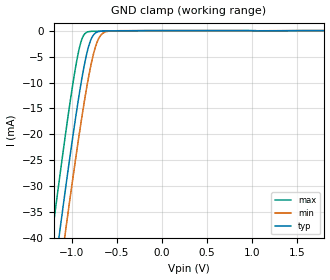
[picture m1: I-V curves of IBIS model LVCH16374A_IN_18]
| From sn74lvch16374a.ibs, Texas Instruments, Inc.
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[Model]   LVCH16374A_IN_18
Model_type  Input
Vinl=0.5775
Vinh=1.2675
| variable   typ   min   max
C_comp   3.69pF   3.02pF   4.47pF
[Temperature Range]   40   100   -40
| Ambient temperature   25   85   -40
[Voltage range]   1.8   1.65   1.95
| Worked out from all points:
|   GND clamp passes 1 mA (typ) near -0.76 V on its own axis
[GND Clamp]
| LVCH16374A_IN_18
|   Voltage   I(typ)   I(min)   I(max)
-5.5V     -656.5mA   -663.3mA   -648.2mA
-1.215V   -49.77mA   -58.01mA   -39.22mA
-1.135V   -39.23mA   -47.47mA   -28.65mA
-1.075V   -31.49mA   -39.7mA    -20.97mA
-1.055V   -28.95mA   -37.15mA   -18.47mA
-955mV    -16.79mA   -24.74mA   -7.045mA
-885mV    -9.193mA   -16.61mA   -1.637mA
-835mV    -4.741mA   -11.3mA    -351.3uA
-785mV    -1.746mA   -6.679mA   -145.9uA
-715mV    -270.3uA   -2.162mA   -107.4uA
-650mV    -78.21uA   -471.6uA   -91.29uA
1.8V      5.126pA    37.8nA     -54.32pA
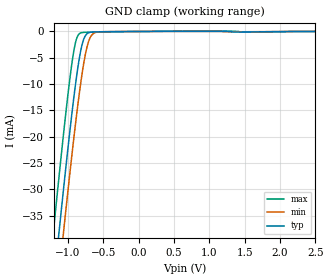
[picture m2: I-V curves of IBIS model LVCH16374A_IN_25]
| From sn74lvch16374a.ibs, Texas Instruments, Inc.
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[Model]   LVCH16374A_IN_25
Model_type  Input
Vinl=0.7
Vinh=1.7
| variable   typ   min   max
C_comp   3.65pF   3.04pF   4.50pF
[Temperature Range]   40   100   -40
| Ambient temperature   25   85   -40
[Voltage range]   2.5   2.3   2.7
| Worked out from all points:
|   GND clamp passes 1 mA (typ) near -0.76 V on its own axis
[GND Clamp]
| LVCH16374A_IN_25
|   Voltage   I(typ)   I(min)   I(max)
-5.5V     -656.6mA   -663.4mA   -648.4mA
-1.205V   -48.49mA   -56.72mA   -37.95mA
-1.13V    -38.62mA   -46.85mA   -28.06mA
-1.07V    -30.89mA   -39.1mA    -20.39mA
-1.055V   -28.99mA   -37.18mA   -18.53mA
-965mV    -17.99mA   -25.98mA   -8.114mA
-885mV    -9.23mA    -16.64mA   -1.681mA
-825mV    -4.04mA    -10.34mA   -313.2uA
-775mV    -1.398mA   -5.9mA     -175.3uA
-710mV    -268.9uA   -1.977mA   -144.6uA
-640mV    -98.59uA   -388.9uA   -125.6uA
2.5V      7.214pA    38.93nA    -770.4pA
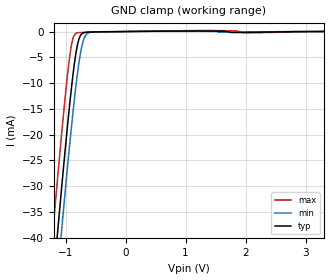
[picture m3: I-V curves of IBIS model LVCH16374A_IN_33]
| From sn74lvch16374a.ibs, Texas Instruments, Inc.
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[Model]   LVCH16374A_IN_33
Model_type  Input
Vinl=0.8
Vinh=2.0
| variable   typ   min   max
C_comp   3.58pF   2.85pF   4.58pF
[Temperature Range]   40   100   -40
| Ambient temperature   25   85   -40
[Voltage range]   3.3   3   3.6
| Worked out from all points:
|   GND clamp passes 1 mA (typ) near -0.76 V on its own axis
[GND Clamp]
| LVCH16374A_IN_33
|   Voltage   I(typ)   I(min)   I(max)
-5.5V     -656.7mA   -663.4mA   -648.5mA
-1.22V    -50.53mA   -58.75mA   -40.01mA
-1.14V    -39.97mA   -48.19mA   -29.42mA
-1.08V    -32.21mA   -40.41mA   -21.7mA
-1.06V    -29.67mA   -37.85mA   -19.2mA
-965mV    -18.03mA   -26.01mA   -8.161mA
-885mV    -9.265mA   -16.67mA   -1.724mA
-830mV    -4.433mA   -10.86mA   -391.1uA
-775mV    -1.429mA   -5.924mA   -215.8uA
-715mV    -330.4uA   -2.212mA   -184.8uA
-640mV    -124.8uA   -410.1uA   -161.8uA
3.3V      9.604pA    40.59nA    -142.9nA
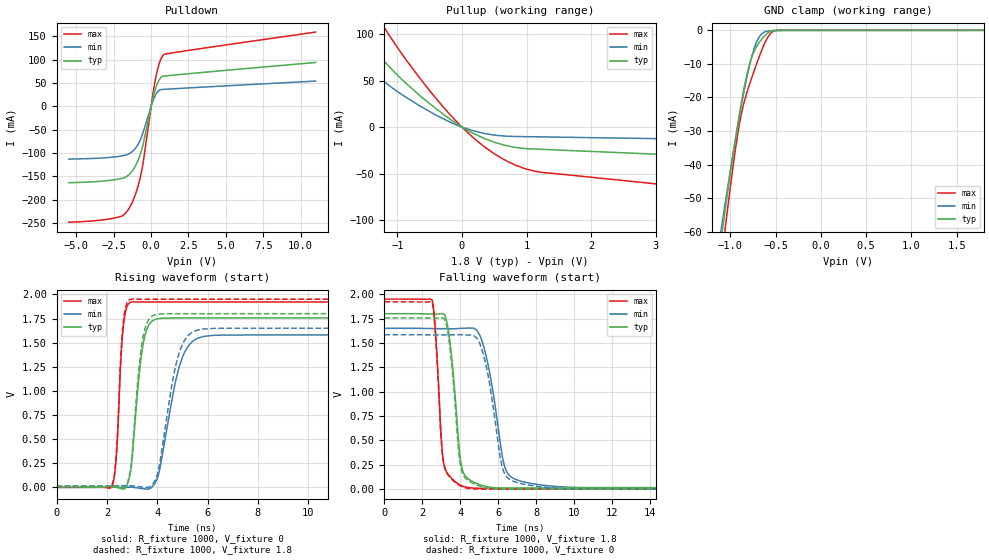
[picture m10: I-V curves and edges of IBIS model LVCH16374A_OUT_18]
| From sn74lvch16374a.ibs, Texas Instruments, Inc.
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[Model]   LVCH16374A_OUT_18
Model_type  3-state
Enable   Active-Low
Vref =   0
Rref =   1000
Cref =   30p
Vmeas =   0.9
| variable   typ   min   max
C_comp   5.26pF   4.69pF   6.09pF
| C_pullup   6.10pF   5.53pF   6.75pF
| C_pulldown   8.32pF   6.62pF   10.15pF
| C_tri-state   5.26pF   4.69pF   6.09pF
[Temperature Range]   40   100   -40
| Ambient temperature   25   85   -40
[Voltage range]   1.8   1.65   1.95
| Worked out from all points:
|   slope of the pulldown table from 0 to 0.27 V, typ, clamps not added: 7.65 ohm
|   slope of the pullup table from 0 to 0.27 V, typ, clamps not added: 27.4 ohm
|   GND clamp passes 1 mA (typ) near -0.60 V on its own axis
|   rising waveform, R_fixture 1000, V_fixture 0: 20-80 % time 372ps typ, 704ps min, 217ps max; typ from 0 V to 1.76 V
|   falling waveform, R_fixture 1000, V_fixture 1.8: 20-80 % time 471ps typ, 803ps min, 336ps max; typ from 1.8 V to 0.012 V
|   rising waveform, R_fixture 1000, V_fixture 1.8: 20-80 % time 356ps typ, 637ps min, 215ps max; typ from 0.012 V to 1.8 V
|   falling waveform, R_fixture 1000, V_fixture 0: 20-80 % time 456ps typ, 758ps min, 333ps max; typ from 1.76 V to 0 V
[GND Clamp]
| LVCH16374A_OUT_18
|   Voltage   I(typ)   I(min)   I(max)
-5.5V     -1.092A    -985.9mA   -1.265A
-1.12V    -65.63mA   -62.5mA    -73.1mA
-1.09V    -59.68mA   -57.14mA   -66.23mA
-1.06V    -53.82mA   -51.86mA   -59.48mA
-1.045V   -50.92mA   -49.25mA   -56.15mA
-960mV    -35.13mA   -34.95mA   -38.34mA
-900mV    -24.87mA   -25.49mA   -27.8mA
-795mV    -10.66mA   -11.13mA   -16.59mA
-735mV    -6.119mA   -5.16mA    -11.82mA
-685mV    -3.765mA   -2.107mA   -8.076mA
-535mV    -84.46uA   -113.4uA   -414.9uA
1.8V      37.82pA    12.05nA    -2.548nA
[Pulldown]
| LVCH16374A_OUT_18
|   Voltage   I(typ)   I(min)   I(max)
-5.5V     -163.6mA   -113mA     -248.3mA
-2.075V   -155.2mA   -106.7mA   -236.5mA
-1.745V   -152.2mA   -104.6mA   -230mA
-1.42V    -144.4mA   -100.5mA   -215.8mA
-1.03V    -126.4mA   -88.99mA   -186.9mA
-695mV    -100.2mA   -69.99mA   -148.2mA
-520mV    -79.1mA    -54.01mA   -118mA
70mV      10.47mA    6.993mA    15.91mA
275mV     35.8mA     23.13mA    55.48mA
565mV     58.22mA    35.03mA    93.73mA
855mV     65.08mA    36.56mA    111.2mA
11V       94.21mA    54.33mA    159.3mA
[Pullup]
| LVCH16374A_OUT_18
|   Voltage   I(typ)   I(min)   I(max)
-5.5V     76.47mA    21.29mA    197.6mA
-4.37V    108.6mA    28.72mA    361.1mA
-3.855V   218mA      37.63mA    399.7mA
-3.525V   246.1mA    54.36mA    367.6mA
-3.375V   237.1mA    101mA      351.9mA
-3.29V    231.5mA    135mA      342.8mA
-2.44V    168.1mA    121.7mA    247.7mA
-1.665V   107.2mA    76.55mA    159.2mA
-1.23V    72.83mA    50.5mA     110mA
-15mV     641.2uA    386.5uA    1.048mA
1.12V     -23.55mA   -10.38mA   -47.39mA
11V       -53.91mA   -20.99mA   -120.9mA
[Ramp]
| LVCH16374A_OUT_18
| variable   typ   min   max
dV/dt_r   1.07/3.86E-10   0.96/7.13E-10   1.16/2.28E-10
dV/dt_f   1.07/4.78E-10   0.98/8.08E-10   1.17/3.40E-10
R_load = 1000
[Rising Waveform]
| LVCH16374A_OUT_18
R_fixture =   1000
C_fixture =   0
L_fixture =   0
V_fixture =   0
V_fixture_min = 0
V_fixture_max = 0
|   Time   V(typ)   V(min)   V(max)
0s        559.4pV    2.27nV     20.29nV
2.21ns    1.77mV     809.6uV    14.88mV
2.385ns   -540.1uV   1.305mV    360.4mV
2.665ns   -18.66mV   2.068mV    1.695V
3.005ns   306.6mV    967uV      1.922V
3.34ns    1.304V     -10.67mV   1.921V
3.64ns    1.669V     -17.95mV   1.921V
5ns       1.756V     1.347V     1.922V
5.98ns    1.756V     1.569V     1.922V
50ns      1.756V     1.58V      1.922V
[Falling Waveform]
| LVCH16374A_OUT_18
R_fixture =   1000
C_fixture =   0
L_fixture =   0
V_fixture =   1.8
V_fixture_min = 1.65
V_fixture_max = 1.95
|   Time   V(typ)   V(min)   V(max)
0s        1.8V       1.65V      1.95V
2.52ns    1.797V     1.647V     1.936V
3.185ns   1.782V     1.646V     223.1mV
3.52ns    1.402V     1.645V     116mV
4.005ns   309.3mV    1.649V     42.17mV
4.36ns    116.5mV    1.652V     18.87mV
5.26ns    32.13mV    1.447V     8.808mV
6.405ns   12.35mV    198.4mV    8.419mV
7.69ns    11.7mV     59.94mV    8.361mV
50ns      11.53mV    15.73mV    8.262mV
[Rising Waveform]
| LVCH16374A_OUT_18
R_fixture =   1000
C_fixture =   0
L_fixture =   0
V_fixture =   1.8
V_fixture_min = 1.65
V_fixture_max = 1.95
|   Time   V(typ)   V(min)   V(max)
0s        11.51mV    15.68mV    8.257mV
2.21ns    13.06mV    16.42mV    24.1mV
2.38ns    10.83mV    16.81mV    368.8mV
2.645ns   -6.565mV   17.33mV    1.692V
2.995ns   316.3mV    16.11mV    1.951V
3.615ns   1.718V     -234.7uV   1.95V
4.045ns   1.795V     177mV      1.95V
4.9ns     1.8V       1.415V     1.95V
5.8ns     1.8V       1.64V      1.95V
50ns      1.8V       1.65V      1.95V
[Falling Waveform]
| LVCH16374A_OUT_18
R_fixture =   1000
C_fixture =   0
L_fixture =   0
V_fixture =   0
V_fixture_min = 0
V_fixture_max = 0
|   Time   V(typ)   V(min)   V(max)
0s        1.758V     1.585V     1.922V
2.52ns    1.755V     1.583V     1.908V
3.175ns   1.738V     1.583V     219.1mV
3.5ns     1.375V     1.583V     112.6mV
3.98ns    283.9mV    1.585V     37.03mV
4.37ns    96.15mV    1.582V     10.47mV
5.23ns    20.32mV    1.374V     560uV
6.3ns     901uV      177.1mV    173.9uV
7.565ns   200uV      42.86mV    104.6uV
50ns      12.16uV    48.19uV    4.972uV
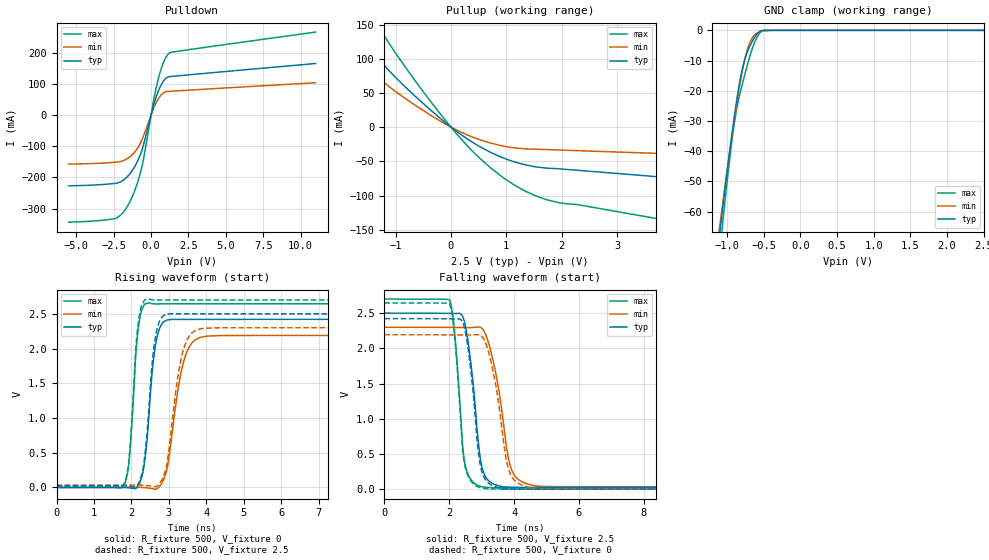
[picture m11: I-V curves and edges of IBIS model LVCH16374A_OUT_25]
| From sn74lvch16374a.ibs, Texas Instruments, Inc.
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[Model]   LVCH16374A_OUT_25
Model_type  3-state
Enable   Active-Low
Vref =   0
Rref =   500
Cref =   30p
Vmeas =   1.25
| variable   typ   min   max
C_comp   5.07pF   4.45pF   6.04pF
| C_pullup   5.99pF   5.35pF   6.80pF
| C_pulldown   7.61pF   6.27pF   8.94pF
| C_tri-state   5.07pF   4.45pF   6.04pF
[Temperature Range]   40   100   -40
| Ambient temperature   25   85   -40
[Voltage range]   2.5   2.3   2.7
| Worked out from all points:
|   slope of the pulldown table from 0 to 0.375 V, typ, clamps not added: 6 ohm
|   slope of the pullup table from 0 to 0.375 V, typ, clamps not added: 17.4 ohm
|   GND clamp passes 1 mA (typ) near -0.58 V on its own axis
|   rising waveform, R_fixture 500, V_fixture 0: 20-80 % time 235ps typ, 363ps min, 187ps max; typ from 0 V to 2.42 V
|   falling waveform, R_fixture 500, V_fixture 2.5: 20-80 % time 327ps typ, 466ps min, 248ps max; typ from 2.5 V to 0.025 V
|   rising waveform, R_fixture 500, V_fixture 2.5: 20-80 % time 228ps typ, 337ps min, 184ps max; typ from 0.025 V to 2.5 V
|   falling waveform, R_fixture 500, V_fixture 0: 20-80 % time 312ps typ, 436ps min, 245ps max; typ from 2.42 V to 0 V
[GND Clamp]
| LVCH16374A_OUT_25
|   Voltage   I(typ)   I(min)   I(max)
-5.5V     -1.136A    -1.03A     -1.309A
-1.105V   -68.29mA   -65.84mA   -74.68mA
-1.075V   -62.09mA   -60.23mA   -67.56mA
-1.045V   -55.98mA   -54.7mA    -60.56mA
-960mV    -39.32mA   -39.55mA   -41.85mA
-905mV    -29.31mA   -30.29mA   -31.46mA
-805mV    -14.26mA   -15.32mA   -19.12mA
-750mV    -8.994mA   -8.844mA   -13.96mA
-690mV    -5.285mA   -4.084mA   -8.679mA
-610mV    -1.821mA   -1.216mA   -3.219mA
-535mV    -123.1uA   -445.7uA   -414.9uA
2.5V      50.37pA    31.77nA    -2.817nA
[Pulldown]
| LVCH16374A_OUT_25
|   Voltage   I(typ)   I(min)   I(max)
-5.5V     -227.2mA   -157.4mA   -343.8mA
-2.45V    -219.5mA   -151.7mA   -332.8mA
-2.015V   -213.6mA   -149mA     -319.9mA
-1.585V   -197.6mA   -139.7mA   -292.7mA
-1.085V   -164.7mA   -118mA     -241.1mA
-650mV    -118.1mA   -84.14mA   -173.1mA
-495mV    -93.16mA   -65.54mA   -137.4mA
190mV     34.44mA    23.84mA    51.4mA
550mV     84.2mA     56.6mA     128mA
880mV     112mA      72.43mA    174.5mA
1.21V     122.9mA    75.8mA     198.2mA
11V       165.1mA    103.4mA    265.9mA
[Pullup]
| LVCH16374A_OUT_25
|   Voltage   I(typ)   I(min)   I(max)
-5.5V     151.9mA    59.5mA     358.9mA
-4.15V    329.2mA    82.51mA    504.8mA
-3.96V    324.4mA    100.6mA    484.4mA
-3.835V   317.5mA    146.7mA    470.4mA
-2.255V   186.8mA    138.7mA    271.3mA
-1.9V     154.1mA    114mA      224.3mA
-1.34V    102.2mA    74.12mA    150.5mA
510mV     -27.96mA   -18.07mA   -44.6mA
1.125V    -50.23mA   -30.08mA   -83.57mA
1.925V    -60.72mA   -33.36mA   -110mA
4.46V     -77.23mA   -40.39mA   -144.2mA
11V       -121.1mA   -58.83mA   -240.2mA
[Ramp]
| LVCH16374A_OUT_25
| variable   typ   min   max
dV/dt_r   1.46/2.42E-10   1.33/3.77E-10   1.60/2.06E-10
dV/dt_f   1.48/3.29E-10   1.36/4.72E-10   1.61/2.62E-10
R_load = 500
[Rising Waveform]
| LVCH16374A_OUT_25
R_fixture =   500
C_fixture =   0
L_fixture =   0
V_fixture =   0
V_fixture_min = 0
V_fixture_max = 0
|   Time   V(typ)   V(min)   V(max)
0s        615.9pV    1.958nV    21.34nV
1.815ns   411.8uV    1.173mV    39.27mV
1.95ns    -6.23mV    1.667mV    451.1mV
2.185ns   26.32mV    2.178mV    2.294V
2.455ns   931.5mV    -8.933mV   2.657V
2.6ns     1.883V     -22.09mV   2.644V
2.78ns    2.322V     33.48mV    2.643V
3.43ns    2.42V      1.873V     2.645V
4.065ns   2.421V     2.181V     2.645V
50ns      2.421V     2.19V      2.645V
[Falling Waveform]
| LVCH16374A_OUT_25
R_fixture =   500
C_fixture =   0
L_fixture =   0
V_fixture =   2.5
V_fixture_min = 2.3
V_fixture_max = 2.7
|   Time   V(typ)   V(min)   V(max)
0s        2.5V       2.3V       2.7V
2.015ns   2.497V     2.297V     2.685V
2.18ns    2.495V     2.297V     2.15V
2.405ns   2.464V     2.296V     652mV
2.61ns    1.992V     2.294V     179.4mV
2.945ns   472.5mV    2.302V     42.92mV
3.11ns    180.9mV    2.208V     27.55mV
3.91ns    27.82mV    290.8mV    18.98mV
4.755ns   25.82mV    42.76mV    18.72mV
50ns      25.46mV    33.49mV    18.58mV
[Rising Waveform]
| LVCH16374A_OUT_25
R_fixture =   500
C_fixture =   0
L_fixture =   0
V_fixture =   2.5
V_fixture_min = 2.3
V_fixture_max = 2.7
|   Time   V(typ)   V(min)   V(max)
0s        25.45mV    33.45mV    18.57mV
1.815ns   25.52mV    34.45mV    59.31mV
1.945ns   19.3mV     34.8mV     458.8mV
2.18ns    50.48mV    35.03mV    2.352V
2.45ns    1.009V     24.33mV    2.713V
2.595ns   1.99V      12.61mV    2.699V
2.765ns   2.41V      62.81mV    2.698V
3.39ns    2.499V     1.984V     2.7V
3.97ns    2.5V       2.292V     2.7V
50ns      2.5V       2.3V       2.7V
[Falling Waveform]
| LVCH16374A_OUT_25
R_fixture =   500
C_fixture =   0
L_fixture =   0
V_fixture =   0
V_fixture_min = 0
V_fixture_max = 0
|   Time   V(typ)   V(min)   V(max)
0s        2.422V     2.194V     2.646V
2.015ns   2.42V      2.192V     2.631V
2.175ns   2.418V     2.192V     2.117V
2.4ns     2.386V     2.191V     629.3mV
2.61ns    1.891V     2.19V      157.3mV
2.905ns   496.4mV    2.194V     29.84mV
3.105ns   139.7mV    2.093V     9.014mV
3.86ns    2.389mV    242.5mV    435.5uV
4.705ns   360uV      8.44mV     153.7uV
50ns      9.698uV    37.07uV    3.865uV
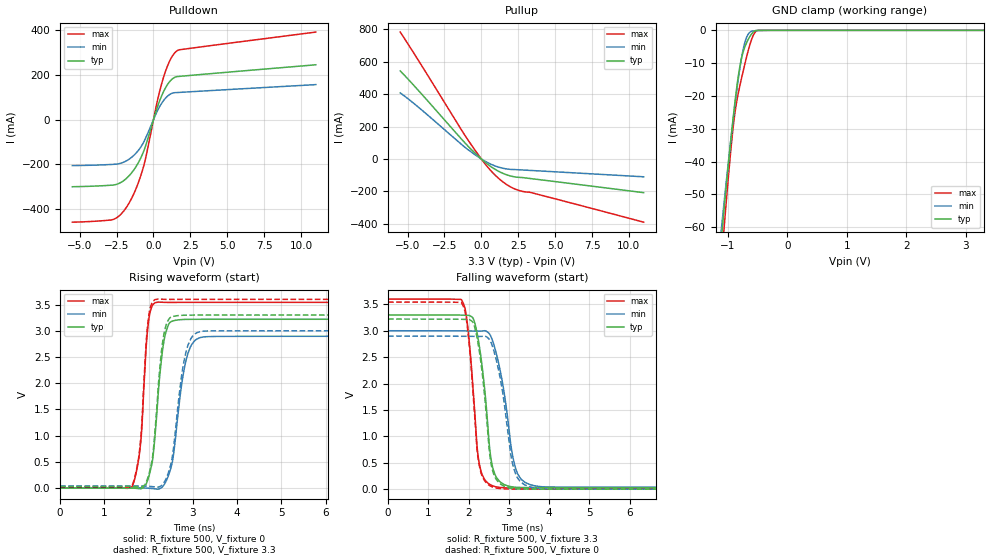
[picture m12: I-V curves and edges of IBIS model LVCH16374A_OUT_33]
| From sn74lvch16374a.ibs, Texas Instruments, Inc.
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[Model]   LVCH16374A_OUT_33
Model_type  3-state
Enable   Active-Low
Vref =   0
Rref =   500
Cref =   50p
Vmeas =   1.5
| variable   typ   min   max
C_comp   4.90pF   4.27pF   6.01pF
| C_pullup   5.99pF   5.17pF   7.14pF
| C_pulldown   7.16pF   5.94pF   8.13pF
| C_tri-state   4.90pF   4.27pF   6.01pF
[Temperature Range]   40   100   -40
| Ambient temperature   25   85   -40
[Voltage range]   3.3   3   3.6
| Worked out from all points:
|   slope of the pulldown table from 0 to 0.495 V, typ, clamps not added: 5.09 ohm
|   slope of the pullup table from 0 to 0.495 V, typ, clamps not added: 13.3 ohm
|   GND clamp passes 1 mA (typ) near -0.60 V on its own axis
|   rising waveform, R_fixture 500, V_fixture 0: 20-80 % time 203ps typ, 263ps min, 157ps max; typ from 0 V to 3.22 V
|   falling waveform, R_fixture 500, V_fixture 3.3: 20-80 % time 258ps typ, 356ps min, 215ps max; typ from 3.3 V to 0.029 V
|   rising waveform, R_fixture 500, V_fixture 3.3: 20-80 % time 194ps typ, 256ps min, 156ps max; typ from 0.029 V to 3.3 V
|   falling waveform, R_fixture 500, V_fixture 0: 20-80 % time 254ps typ, 340ps min, 213ps max; typ from 3.22 V to 0 V
[GND Clamp]
| LVCH16374A_OUT_33
|   Voltage   I(typ)   I(min)   I(max)
-5.5V     -1.092A    -985.9mA   -1.265A
-1.13V    -67.63mA   -64.3mA    -75.42mA
-1.095V   -60.66mA   -58.03mA   -67.37mA
-1.065V   -54.79mA   -52.74mA   -60.59mA
-910mV    -26.51mA   -27.02mA   -29.36mA
-865mV    -19.44mA   -20.32mA   -23.16mA
-795mV    -10.66mA   -11.13mA   -16.59mA
-740mV    -6.406mA   -5.567mA   -12.21mA
-680mV    -3.568mA   -1.9mA     -7.713mA
-600mV    -1.079mA   -275.4uA   -2.703mA
-520mV    -35.47uA   -95.17uA   -168.9uA
3.3V      64.71pA    54.64nA    -3.114nA
[Pulldown]
| LVCH16374A_OUT_33
|   Voltage   I(typ)   I(min)   I(max)
-5.5V     -300mA     -205.4mA   -458.6mA
-2.76V    -292.7mA   -199.9mA   -447mA
-2.24V    -282mA     -195.3mA   -425mA
-1.72V    -255.5mA   -179.7mA   -380.4mA
-1.16V    -207.6mA   -148.1mA   -305.1mA
-670mV    -142.6mA   -101.5mA   -209.1mA
-500mV    -110.4mA   -77.62mA   -163.1mA
255mV     54.31mA    37.86mA    80.86mA
710mV     129mA      87.77mA    195.2mA
1.135V    173mA      114mA      267.3mA
1.56V     192.2mA    121.2mA    306.1mA
11V       245.5mA    156.8mA    391.8mA
[Pullup]
| LVCH16374A_OUT_33
|   Voltage   I(typ)   I(min)   I(max)
-5.5V     543.9mA    408.1mA    783.4mA
-4.21V    417.2mA    315.3mA    600.1mA
-875mV    76.67mA    55.83mA    113mA
385mV     -29.48mA   -20.35mA   -45.09mA
900mV     -62.02mA   -41.59mA   -96.63mA
1.41V     -86.5mA    -55.9mA    -137.8mA
2.005V    -105.3mA   -64.13mA   -173.4mA
2.595V    -113.6mA   -66.73mA   -195.4mA
3.255V    -119.7mA   -70.08mA   -204.5mA
11V       -207.7mA   -109.8mA   -389.9mA
[Ramp]
| LVCH16374A_OUT_33
| variable   typ   min   max
dV/dt_r   1.94/2.09E-10   1.75/2.70E-10   2.13/1.64E-10
dV/dt_f   1.96/2.62E-10   1.78/3.64E-10   2.15/2.22E-10
R_load = 500
[Rising Waveform]
| LVCH16374A_OUT_33
R_fixture =   500
C_fixture =   0
L_fixture =   0
V_fixture =   0
V_fixture_min = 0
V_fixture_max = 0
|   Time   V(typ)   V(min)   V(max)
0s        789.4pV    1.869nV    21.43nV
1.62ns    -559.7uV   1.595mV    18.15mV
1.82ns    -14.79mV   2.4mV      871.2mV
2.005ns   225.5mV    -5.475mV   3.223V
2.215ns   1.787V     -21.43mV   3.547V
2.33ns    2.724V     40.52mV    3.543V
2.465ns   3.142V     282.3mV    3.541V
2.855ns   3.217V     2.472V     3.542V
3.275ns   3.22V      2.886V     3.542V
50ns      3.22V      2.895V     3.542V
[Falling Waveform]
| LVCH16374A_OUT_33
R_fixture =   500
C_fixture =   0
L_fixture =   0
V_fixture =   3.3
V_fixture_min = 3
V_fixture_max = 3.6
|   Time   V(typ)   V(min)   V(max)
0s        3.3V       3V         3.6V
1.82ns    3.296V     2.997V     3.589V
1.96ns    3.292V     2.996V     3.189V
2.11ns    3.241V     2.995V     1.909V
2.31ns    2.48V      2.994V     335.4mV
2.56ns    558.2mV    2.881V     76.26mV
2.8ns     127.7mV    2.186V     30.82mV
3.19ns    35.39mV    343.2mV    22.15mV
3.835ns   29.17mV    44.97mV    21.34mV
50ns      28.59mV    36.93mV    21.11mV
[Rising Waveform]
| LVCH16374A_OUT_33
R_fixture =   500
C_fixture =   0
L_fixture =   0
V_fixture =   3.3
V_fixture_min = 3
V_fixture_max = 3.6
|   Time   V(typ)   V(min)   V(max)
0s        28.58mV    36.89mV    21.11mV
1.62ns    27.8mV     38.29mV    39.99mV
1.81ns    13.81mV    38.92mV    846.2mV
2.005ns   262.6mV    30.95mV    3.301V
2.21ns    1.847V     15.49mV    3.605V
2.32ns    2.81V      71.18mV    3.602V
2.455ns   3.22V      317.9mV    3.599V
2.85ns    3.298V     2.615V     3.6V
3.265ns   3.3V       2.995V     3.6V
50ns      3.3V       3V         3.6V
[Falling Waveform]
| LVCH16374A_OUT_33
R_fixture =   500
C_fixture =   0
L_fixture =   0
V_fixture =   0
V_fixture_min = 0
V_fixture_max = 0
|   Time   V(typ)   V(min)   V(max)
0s        3.221V     2.898V     3.543V
1.82ns    3.217V     2.895V     3.532V
1.96ns    3.213V     2.895V     3.13V
2.11ns    3.16V      2.894V     1.821V
2.31ns    2.375V     2.893V     303.9mV
2.55ns    519.5mV    2.789V     57.49mV
2.795ns   94.94mV    2.058V     9.772mV
3.17ns    6.956mV    286.1mV    1.106mV
3.82ns    544uV      6.788mV    228.8uV
50ns      9.732uV    38.3uV     3.492uV
